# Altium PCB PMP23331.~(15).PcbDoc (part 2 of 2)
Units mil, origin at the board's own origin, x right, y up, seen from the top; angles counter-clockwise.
Board outline 3600 x 3375 mil, 4 copper layers (Top Layer, Signal Layer 1, Signal Layer 2, Bottom Layer), stack 39.6 mil thick; 105 components, 60 nets, 267 pads, 76 vias.

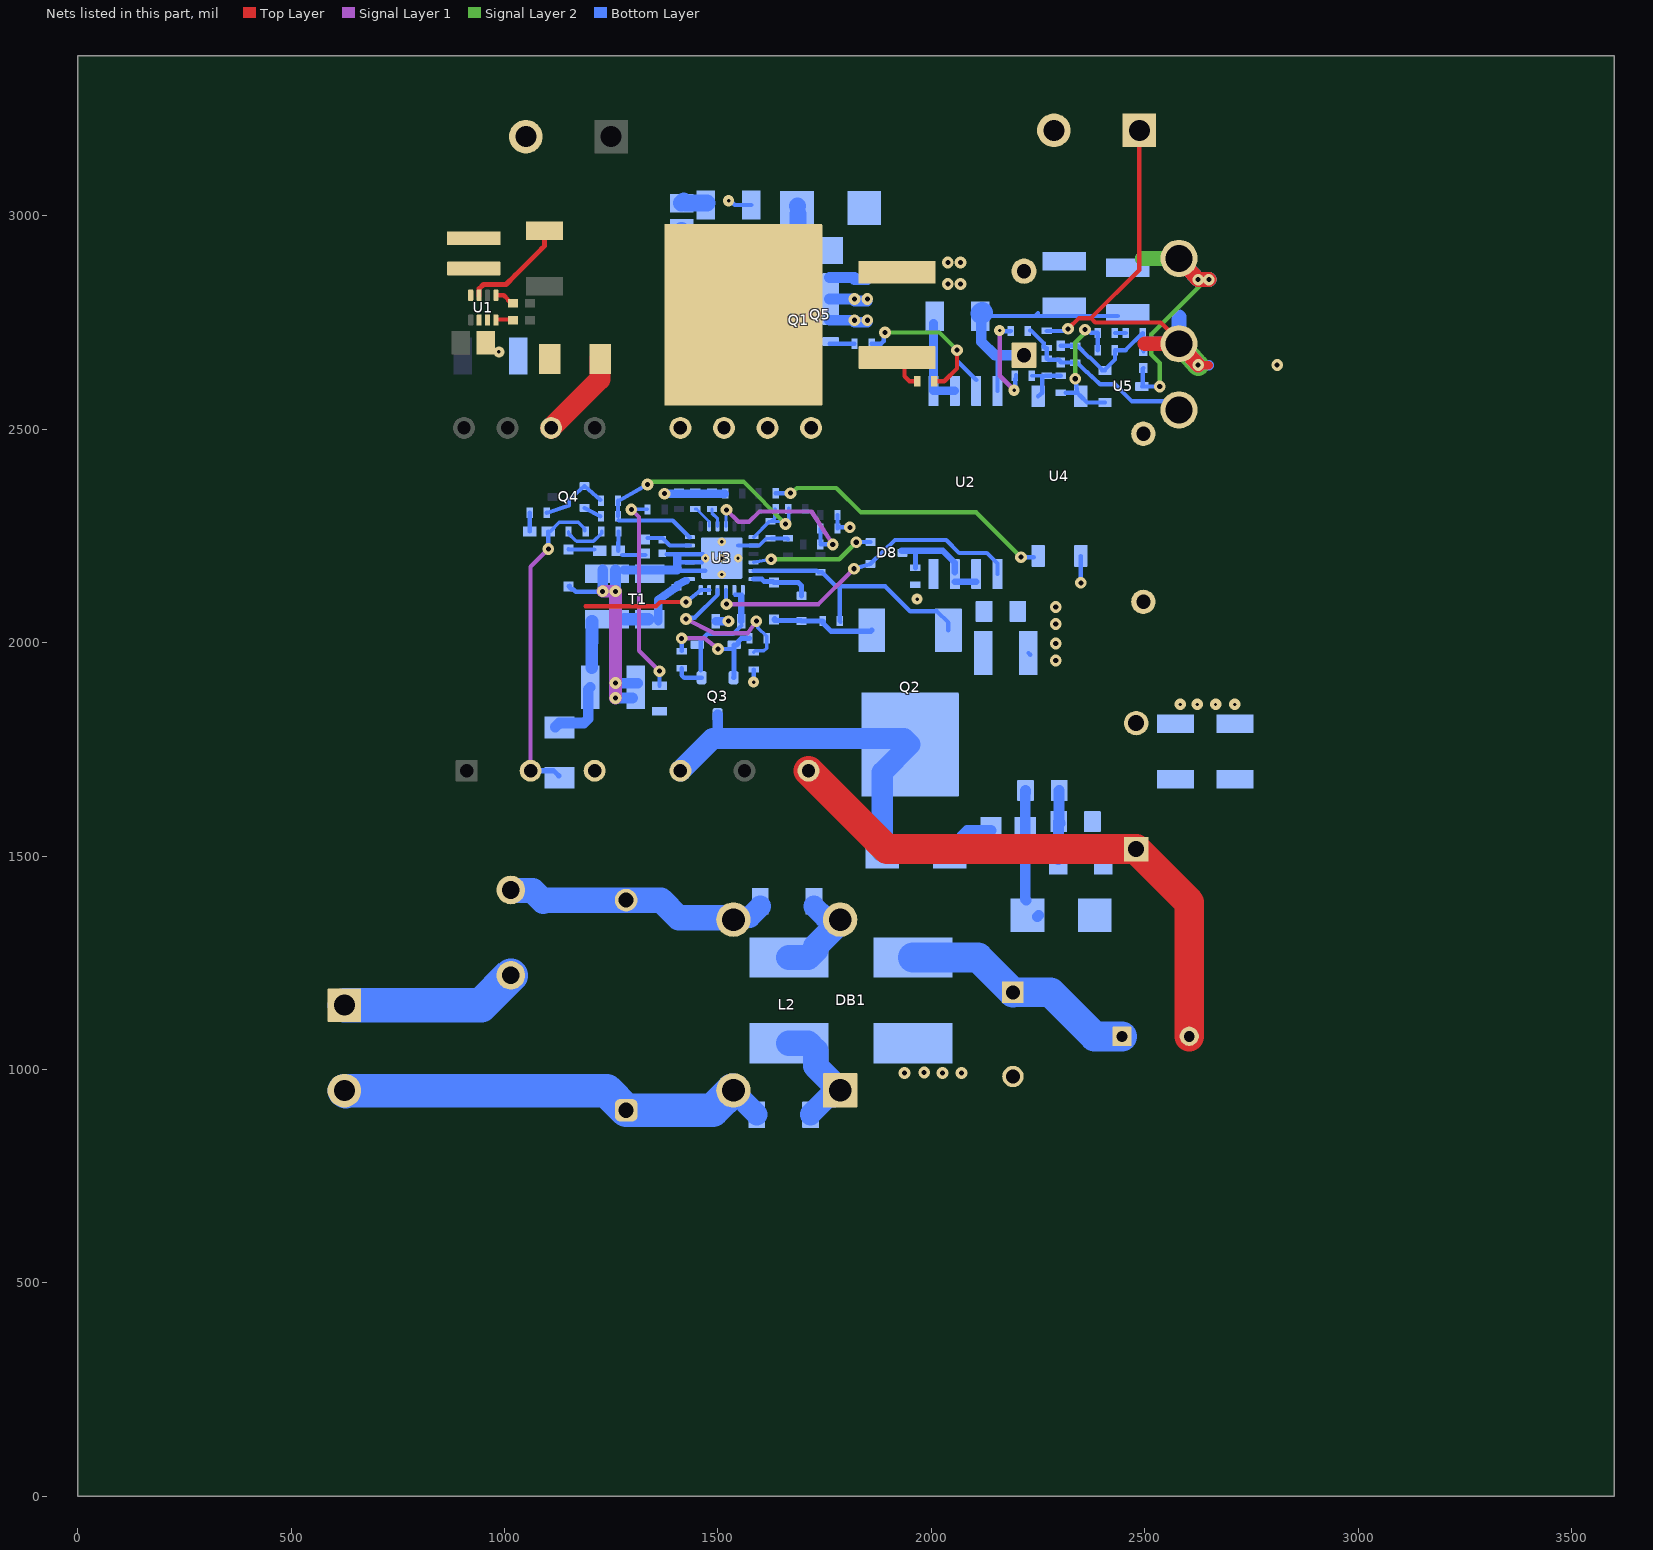
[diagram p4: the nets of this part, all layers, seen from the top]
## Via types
v1: diameter 27.56, hole 11.81, Top Layer to Bottom Layer, tented both sides, 30 vias
v2: diameter 27.56, hole 11.81, Top Layer to Bottom Layer, tented top, 22 vias
v3: diameter 26, hole 8, Top Layer to Bottom Layer, tented both sides, 11 vias
v4: diameter 19.68, hole 7.87, Top Layer to Bottom Layer, 5 vias
v5: diameter 27, hole 8, Top Layer to Bottom Layer, tented both sides, 4 vias
v6: diameter 27.56, hole 11.81, Top Layer to Bottom Layer, 4 vias

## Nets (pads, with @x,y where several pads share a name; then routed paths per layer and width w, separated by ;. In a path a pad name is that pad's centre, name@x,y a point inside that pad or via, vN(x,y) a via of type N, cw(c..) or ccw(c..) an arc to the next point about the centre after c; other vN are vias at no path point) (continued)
GND_P: C1.2 C3.1 C4.1 C5.1 C7.2 C13.1 C16.1 C17.2 C18.2 C19.1 C21.2 C23.2 C25.2 C26.2 C27.1 C31.2 D11.1 DB1.4 R10.2 R11.1 R22.1 R25.2 R29.1 R31.1 R34.1 RT1.2 T1.3 U2.4 U3.8 U3.17 U3.18 U3.20 U3.21 U3.22 U3.25 U4.4 | length 1676
  Top Layer w10: 1190,2085 1355,2085 1365,2095 v1(1425,2095)
  Signal Layer 1 w30: v2(1230,2120) v2(1260,2120) v2(1260,1870)
  Bottom Layer w7.87: C31.2@1612.58,2243.67 C31.2@1624.99,2243.67
  Bottom Layer w8: 1596.16,2227.25 C31.2@1612.58,2243.67
  Bottom Layer w8.66: U3.21@1434.16,2187.49 U3.21@1434.16,2187.88
  Bottom Layer w10: D11.1@1150,2131.69 D11.1@1151.69,2130 ; D11.1@1153,2133 1153,2128.69 1156.81,2124.88 1161.12,2124.88 1167,2119 v2@1230,2119 ; 1380,2207 U3.25@1465,2207 ; 1405,2188 U3.25@1462.6,2188 ; C17.2@1413.2,2168.2 U3.25@1470,2168.2 ; v1(1425,2095) U3.18@1459.75,2122.92 U3.17@1479.44,2122.92 ; C26.2@1516.51,2348.67 C26.2@1517.14,2349.3 ; U3.25@1547.35,2227.25 1596.16,2227.25 ; v3(1583.77,1907.47) C16.1@1583.77,1937 ; C31.2@1624.99,2243.67 1662.21,2243.67 C25.2@1664.11,2241.77 ; R34.1@1780,2267 R25.2@1780,2299 ; R34.1@1780,2270 v1(1809,2270) ; R11.1@2227.39,1975.71 R11.1@2231.46,1971.64 ; v2(2350,2140) U4.4@2350,2202.99
  Bottom Layer w20: C19.1@1280,2170 1405,2170 1405,2201.74 ; v1(1375,2348.67) C26.2@1516.51,2348.67 ; C23.2@1495,2050 v1(1525,2050)
  Bottom Layer w25: v2(1230,2120) C19.1@1230,2170 ; v2(1260,1870) C13.1@1300,1870 ; v2(1260,1905) C13.1@1312.35,1905 ; v2(1260,2120) C19.1@1260,2170
  other v2: 1936.75,992.02 2026.32,992.02 2070.71,992.02 1983.18,992.75 2291.34,1957.84 2291.34,1998.03 2291.34,2043.52 2291.34,2083.46
  other v3: 1966.65,2101.69
  other v4: 1508.96,2159.54 1470.78,2197.72 1508.96,2197.72 1547.15,2197.72 1508.96,2235.91
  other v5: 2582.5,1855 2622.5,1855 2665.6,1855 2711.01,1855
GND_S: C1.1 C8.2 C9.2 C10.2 C11.1 C20.2 D4.2 J2.2 Q1.1-2-3 Q5.3 R4.1 R36.1 TP2.1 U2.5 U2.6 U5.3 | length 1467.1
  Top Layer w35: TP2.1@2580,2900 v6(2625,2850) v6(2650,2850)
  Signal Layer 1 w35: TP2.1@2580,2900 v6(2625,2850) v6(2650,2850)
  Signal Layer 2 w10: v1(2535,2600) 2535,2655 2515,2675 2515,2722 v6@2641.5,2848.5
  Signal Layer 2 w35: 2495,2900 TP2.1@2580,2900 v6(2625,2850) v6(2650,2850)
  Bottom Layer w10: v3(1525,3035) 1529.33,3035 1539.33,3025 R4.1@1578.15,3025 ; R36.1@2496.65,2643.31 2494.98,2641.63 2494.98,2601.67 U5.3@2493.31,2600 v1(2535,2600)
  Bottom Layer w20: C20.2@2005,2748.43 U2.5@2005,2589.57 U2.6@2055,2589.57
  Bottom Layer w25: Q1.1-2-3@1761.22,2755 v2(1820,2755) ; Q1.1-2-3@1761.22,2805 v2(1820,2805) ; Q1.1-2-3@1761.22,2855 1820,2855 ; v2@1820,2750 v2@1850,2750 ; v2@1820,2800 v2@1850,2800 ; 1820,2850 1850,2850 ; v6(2625,2850) v6(2650,2850)
  Bottom Layer w35: 2495,2900 TP2.1@2580,2900 v6(2625,2850)
  other v2: 1850,2755 1850,2805 2038.5,2840.05 2068.5,2840.05 2038.5,2890.05 2068.5,2890.05
IPC: R32.1 R34.2 U3.4 | length 418
  Signal Layer 1 w10: v1(1519.8,2310.91) 1548,2283 1572.52,2283 1597.27,2307 1719,2307 v1(1769,2230)
  Bottom Layer w7.87: U3.4@1518.81,2272.53 1518.81,2309.92 v1(1519.8,2310.91)
  Bottom Layer w10: R32.1@1740,2230 v1@1775,2230 ; R32.1@1740,2235 R34.2@1740,2267
NetC2_2: C2.2 R1.1 R2.2 | length 164.3
  Bottom Layer w25: C2.2@2296.85,1490.98 2297.61,1491.74 2297.61,1579.92 R1.1@2298.38,1580.68 2298.02,1581.04 2298.87,1581.89 2298.87,1652.93 R2.2@2299.37,1653.43 ; R1.1@2301.33,1576.9 R1.1@2301.69,1577.26
NetC6_1: C6.1 J1.2 L2.2 R38.1 | length 1033.3
  Bottom Layer w50: L2.2@1536.31,951.02 1536.31,949.88 1591.01,895.18 R38.1@1591.01,894
  Bottom Layer w78.74: J1.2@627.75,947.72 J1.2@625,950.47 1238.94,950.47 C6.1@1285,904.41 1487.41,904.41 1533.65,950.65 1535.93,950.65 L2.2@1536.31,951.02
NetC6_2: C6.2 F1.1 L2.3 R37.1 | length 629
  Bottom Layer w50: L2.3@1536.31,1351.02 1542.18,1356.9 1574.3,1356.9 1599.21,1381.82 R37.1@1599.21,1383
  Bottom Layer w59.06: F1.1@1015,1420.47 1016.51,1418.97 1066.03,1418.97 1091,1394 1093.54,1396.54 C6.2@1285,1396.54 1366.83,1396.54 1408.19,1355.17 1532.16,1355.17 L2.3@1536.31,1351.02
NetC7_1: C7.1 DB1.1 L1.1 | length 566.3
  Bottom Layer w70: DB1.1@1957.34,1262.25 2109.18,1262.25 C7.1@2191,1180.43 ; C7.1@2190.68,1180.99 2279.01,1180.99 2382.35,1077.65 L1.1@2446.59,1077.65
NetC11_2: C11.2 C12.2 D4.1 Q1.5-6-7-8 Q5.4 T1.9 T1.10 | length 259.4
  Bottom Layer w39.37: 1415,2864 C12.2@1415,2965 ; 1429,2863 1451,2841 1451,2833 ; D4.1@1686.63,3022.63 D4.1@1687,3023 ; D4.1@1687.26,2987 1687.26,3003.26 1687.63,3003.63 1687.63,2906.37 C11.2@1691,2903
NetC12_1: C12.1 R4.2 | length 64.6
  Bottom Layer w39.37: C12.1@1415,3029.53 1415,3030 1420,3035 1425,3030 R4.2@1475,3030
NetC14_1: C14.1 C15.1 D6.1 U1.6 U1.7
  other v3: 987,2681
NetC21_1: C21.1 D8.3 U2.2 U2.3 | length 249.6
  Bottom Layer w12: 1960,2215 1962.37,2212.63 C21.1@1962.37,2175
  Bottom Layer w15: D8.3@1930,2215 1960,2215 2027,2215 2055,2186.94 U2.3@2055,2165 ; U2.3@2055,2142 U2.2@2105,2142
NetC24_1: C24.1 R28.2 | length 212.6
  Signal Layer 1 w10: v3@2159,2732 v3(2160,2731) 2160,2625 v3(2194,2591)
  Bottom Layer w10: v3@2167,2729 2185,2729 C24.1@2186,2730 ; v3(2194,2591) 2196.68,2593.68 2196.68,2617.47 2198,2618.79 R28.2@2198,2627
NetC28_1: C28.1 C29.2 R30.1 R35.2 R36.2 U5.2 | length 314.7
  Bottom Layer w10: R30.1@2303.15,2695.35 2303.31,2695.51 C28.1@2333.09,2695.51 ; C28.1@2337.06,2695.67 2333.25,2695.67 C28.1@2333.09,2695.51 ; R36.2@2496.65,2682.68 2496.65,2684.65 2495.83,2685.47 2495.83,2724.17 R35.2@2495,2725 2455,2685 C29.2@2430,2685 2430,2663.13 2406.69,2639.82 U5.2@2406.69,2637.4 2399.71,2637.4 2399.71,2639.46 2371.5,2667.67 2369.55,2667.67 2341.72,2695.51 C28.1@2333.09,2695.51
NetC29_1: C29.1 C30.2 R33.1 U4.3 U5.1 | length 331
  Signal Layer 2 w10: v1(2337,2618) 2337.09,2703 2360,2725.91 v1(2360,2733)
  Bottom Layer w10: R33.1@2315,2585 U4.3@2342.01,2585 ; v1(2337,2618) U4.3@2342.01,2585 ; v1(2360,2733) 2373.02,2725.91 2389.09,2725.91 C30.2@2390,2725 C29.1@2390,2685 ; U5.1@2406.69,2562.6 2364.41,2562.6 U4.3@2350,2577.01 U4.3@2342.01,2585
NetC30_1: C30.1 R35.1 | length 25
  Bottom Layer w10: C30.1@2430,2725 R35.1@2455,2725
NetD1_1: D1.1 R2.1 R3.2 | length 268.4
  Bottom Layer w25: R2.1@2220.63,1648.51 R2.1@2220.63,1653.43 2220.21,1653.01 2220.21,1560.29 R3.2@2219.8,1559.88 2219.8,1399.33 D1.1@2222.59,1396.54 ; D1.1@2248,1357.37 D1.1@2251.63,1361
NetD2_1: D2.1 R3.1 | length 121.9
  Bottom Layer w25: D2.1@2042.74,1510.66 2069.61,1537.53 2069.61,1545.23 2084.26,1559.88 R3.1@2139.8,1559.88
NetD5_2: D5.2 Q2.1 R6.2 R7.2 | length 246.9
  Bottom Layer w12: D5.2@1632.97,2055.66 D5.2@1631,2053.69 1632.61,2052.08 1694.39,2052.08 R6.2@1696,2050.47 R7.2@1745.07,2050.47 1746.57,2048.97 1746.57,2044.47 1764.57,2026.47 1857.85,2026.47 Q2.1@1860.24,2028.86
NetD6_2: D6.2 T1.12 | length 213.4
  Top Layer w25: D6.2@1224.26,2664.48 D6.2@1227.11,2661.63
  Top Layer w50: T1.12@1109.21,2502.75 1223.67,2617.21 1223.67,2663.89 D6.2@1224.26,2664.48
NetD7_1: D7.1 Q3.2 R8.1 R12.2 | length 280.8
  Signal Layer 1 w10: v1(1415,2010) 1468.25,2010 v1(1500,1985)
  Bottom Layer w10: R8.1@1415,1980 v1(1415,2010) ; v1(1500,1985) 1535,1985
  Bottom Layer w12: Q3.2@1536.6,1917.76 1537.45,1918.61 1537.45,1994.15 1543.36,1994.15 1548.06,1998.84 1548.06,2002.97 1555.08,2010 R12.2@1573.9,2010
NetD9_1: D9.1 R17.2 R19.2 | length 99
  Bottom Layer w10: D9.1@1266.65,2215 R17.2@1267,2260 ; D9.1@1276,2205 R19.2@1330,2205
NetD9_2: D9.2 D11.2 | length 60
  Bottom Layer w10: D11.2@1150,2218.31 D9.2@1210,2218
NetD10_1: D10.1 R20.2 | length 44
  Bottom Layer w10: R20.2@1059,2304 D10.1@1059.35,2260
NetDB1_2: DB1.2 L2.4 R37.2 | length 240.2
  Bottom Layer w50: R37.2@1725.2,1383 1725.2,1381.82 1750.12,1356.9 1780.43,1356.9 L2.4@1786.31,1351.02
  Bottom Layer w59.06: DB1.2@1666,1262.25 1711.28,1262.25 1728.99,1279.96 1728.99,1287.85 1786.31,1345.16 L2.4@1786.31,1351.02
NetDB1_3: DB1.3 L2.1 R38.2 | length 280.4
  Bottom Layer w50: R38.2@1716.99,894 1716.99,895.18 1757.48,935.67 1770.95,935.67 L2.1@1786.31,951.02
  Bottom Layer w59.06: DB1.3@1666,1061.46 1711.28,1061.46 1728.99,1043.74 1728.99,1008.34 L2.1@1786.31,951.02
NetF1_2: F1.2 J1.1 | length 419
  Bottom Layer w80: J1.1@625,1150.47 945,1150.47 F1.2@1015,1220.47
NetL3_1: L3.1 U1.4
NetQ1_4: Q1.4 R5.2 | length 58.8
  Bottom Layer w10: Q1.4@1761.22,2700 R5.2@1820,2700
NetQ4_1: Q4.1 R16.2 R20.1 | length 166.2
  Bottom Layer w10: R20.1@1099,2304 1150.94,2321 1150.94,2335 Q4.1@1187.42,2366.59 R16.2@1224.37,2334
NetQ4_2: Q4.2 R15.2 | length 41.7
  Bottom Layer w10: Q4.2@1187.42,2315.41 R15.2@1224.37,2296
NetQ5_1: Q5.1 R39.2 | length 87
  Top Layer w10: Q5.1@1937,2676 1937,2624 1949,2612 R39.2@1967,2612
NetR9_2: R9.2 U1.1 | length 43.6
  Top Layer w10: U1.1@980,2813.62 998.2,2813.62 1008.5,2803.31 1008.5,2801.34 1013.35,2796.5 R9.2@1015.31,2796.5
NetR13_2: R13.2 U1.8 | length 37
  Top Layer w10: U1.8@980,2755.35 980,2756.03 980.91,2756.93 1013.69,2756.93 R13.2@1015.28,2758.51
NetR14_1: R14.1 R17.1 | length 102.7
  Bottom Layer w8: R14.1@1150,2260 1150,2255.5 1165.38,2240.12 1165.95,2240.12 1169.07,2237 1208.5,2237 1228,2256.5 R17.1@1228,2261
NetR26_1: R26.1 R28.1 R33.2 U4.1 | length 121
  Bottom Layer w7.87: R28.1@2235,2625 2260,2625 R26.1@2267,2625
  Bottom Layer w10: U4.1@2250,2577.01 2260,2585 R26.1@2260,2625 ; R26.1@2267,2625 R26.1@2270,2625 R33.2@2303.15,2625
OPTO_C: R21.2 U4.6 | length 676
  Signal Layer 2 w10: v1(1670,2350) 1685,2362 1777,2362 1835,2305 2105,2305 v2(2210,2200)
  Bottom Layer w10: R21.2@1635,2350 v1(1670,2350) ; v2(2210,2200) U4.6@2240,2200
P13: C23.1 D7.2 Q3.1 R8.2 U3.13 U3.14 | length 320.3
  Bottom Layer w10: R8.2@1415,1940 1415,1923.61 1420.86,1917.76 Q3.1@1461.79,1917.76 ; 1460,1935 1460,2005 1475,2020 1535,2020 C23.1@1555,2040 ; U3.14@1540,2112 U3.13@1556.22,2111.97
  Bottom Layer w15: C23.1@1555,2050 1555,2109
PWML: D5.1 R6.1 U3.12 | length 142.3
  Bottom Layer w12: U3.12@1583.77,2148.51 1602.65,2148.51 1608.39,2142.77 1628.53,2142.77 D5.1@1631,2140.31 1688.97,2140.31 1696,2133.28 R6.1@1696,2109.53
QLSRC: Q2.3 R7.1 R10.1 R11.2 R23.2 U3.11 | length 609.1
  Bottom Layer w10: U3.11@1583.77,2168.2 1731.71,2168.2 1735.5,2164.41 R23.2@1740,2164.41 1744.5,2164.41 1777.22,2131.69 1787.5,2131.69 ; R7.1@1787.04,2048.5 R7.1@1785.07,2050.47 1785.07,2129.27 1787.5,2131.69 ; Q2.3@2039.76,2028.86 2039.76,2046.65 2013.27,2073.15 1950.45,2073.15 1891.91,2131.69 1787.5,2131.69
RDM: R31.2 U3.3 | length 45.8
  Bottom Layer w7.87: R31.2@1485.96,2312.88 1485.96,2303.52 1499.12,2290.36 U3.3@1499.12,2272.53
REF: C22.1 C31.1 R15.1 R16.1 R24.1 U3.7 U3.24 | length 839.7
  Signal Layer 2 w9.84: 1560,2377 v1(1658,2278) ; v1@1659.44,2269.49 v1@1664.53,2274.58
  Signal Layer 2 w10: v1@1340,2377 1560,2377
  Bottom Layer w8: U3.7@1583.77,2246.94 1620.5,2283.67 C31.1@1624.99,2283.67 ; C22.1@1634.9,2312.88 1632.61,2312.88 1632.61,2291.29 C31.1@1624.99,2283.67 ; R24.1@1665.76,2314.85 1665.76,2275.81 1664.53,2274.58 1655.44,2283.67 C31.1@1624.99,2283.67
  Bottom Layer w9.84: U3.24@1432.72,2246.94 U3.24@1434.16,2246.94
  Bottom Layer w10: R15.1@1266,2296 R16.1@1266,2332 ; R16.1@1266,2331 v1(1335,2370) ; R15.1@1267.65,2286 1394,2286 U3.24@1432.72,2246.94
RT1_1: R27.1 RT1.1 | length 487.6
  Signal Layer 1 w9.84: v1(1297,2312) 1315,2294 ; v1@1297.34,2310.91 v1@1306.49,2310.91
  Signal Layer 1 w10: 1315,2294 1315,1981 v1(1363,1933)
  Bottom Layer w8: v1(1297,2312) R27.1@1335,2312
  Bottom Layer w10: RT1.1@1362.93,1898.9 v1(1363,1933)
RTZ: R29.2 U3.2 | length 56
  Bottom Layer w6: R29.2@1446.59,2312.88 1450.15,2312.88 1479.44,2283.59 U3.2@1479.44,2272.53
RUN: D8.2 U3.10 | length 301.1
  Signal Layer 2 w9.84: v1(1624.74,2195.03) 1784,2195
  Signal Layer 2 w10: 1784,2195.03 v1(1824,2235)
  Bottom Layer w7.87: U3.10@1583.77,2187.88 v1(1624.74,2195.03) v1@1617.59,2187.88
  Bottom Layer w10: v1(1824,2235) D8.2@1857.6,2235.59
SR_DRV: R5.1 R39.1 U2.7 | length 440.6
  Top Layer w10: R39.1@2004.5,2614.5 R39.1@2007,2612 ; R39.1@2005,2612 R39.1@2007,2612 ; v1(2060,2685) 2060,2642 2030,2612 R39.1@2007,2612
  Signal Layer 2 w10: v1(1891.51,2726.26) 2018.74,2726.26 v1(2060,2685)
  Bottom Layer w10: R5.1@1860,2700 1882.29,2700 1888.15,2705.86 1888.15,2722.9 v1(1891.51,2726.26) ; v1(2060,2685) 2060,2660 U2.7@2105,2615
SRDRV: D8.1 U2.1 U3.15 | length 773.7
  Signal Layer 1 w10: v1(1520,2090) 1735.67,2090 v1(1818.64,2172.96)
  Bottom Layer w10: v1@1519,2090 U3.15@1519,2123 ; v1(1818.64,2172.96) D8.1@1857.6,2184.41 1915,2240 2035,2240 2065,2210 2130,2210 U2.1@2155,2185 ; U2.1@2155,2160.43 U2.1@2155,2184.84
SWS: C16.2 R12.1 U3.16 | length 403.4
  Signal Layer 1 w10: v1(1425,2055) 1490,2022 1570,2022 v1(1590,2050)
  Bottom Layer w8: C16.2@1583.77,1977 1587.27,1980.5 1607.58,1980.5 1613.9,1986.82 R12.1@1613.9,2010 1613.9,2014.5 1593.74,2034.66 1593.74,2046.26 v1(1590,2050)
  Bottom Layer w10: v1(1425,2055) 1428.36,2058.36 1445.8,2058.36 1499.12,2111.68 U3.16@1499.12,2122.92
Vaux: D3.2 D10.2 R14.2 T1.2 | length 760
  Signal Layer 1 w10: T1.2@1061.21,1699.75 1061.21,2177.55 v1(1102.65,2219)
  Bottom Layer w8: D10.2@1102.65,2260 1106.59,2260 1128.59,2282 1172.5,2282 1188,2266.5 R14.2@1188,2262
  Bottom Layer w10: T1.2@1058.56,1686.84 T1.2@1065.13,1686.84 ; v1(1102.65,2219) D10.2@1102.65,2260
  Bottom Layer w12: T1.2@1061.21,1699.75 1115.25,1699.75 D3.2@1127,1688
Vbulk: C2.1 C3.2 C4.2 C5.2 D1.2 L1.2 R1.2 T1.6 | length 1333.6
  Top Layer w70: T1.6@1712.21,1699.75 1895.93,1516.03 C5.2@2479.8,1516.03 2604.07,1391.76 L1.2@2604.07,1077.65
VDD: C13.2 C17.1 C18.1 C19.2 D3.1 U3.19 | length 451.9
  Bottom Layer w18: C17.1@1405,2135 U3.19@1425,2145
  Bottom Layer w20: C18.1@1360,2050 1360,2100 C17.1@1403,2130
  Bottom Layer w25: D3.1@1119,1802.06 1128.41,1811.46 1185.78,1811.46 1196.18,1821.86 1196.18,1890.19 C13.2@1201,1895 ; D3.1@1126.34,1808.29 D3.1@1128.75,1810.7
  Bottom Layer w30: C13.2@1204.46,1941.82 C19.2@1205,2050 ; C19.2@1281.04,2054.85 C18.1@1336.04,2054.85
VOUT: C8.1 C9.1 C10.1 C20.1 J2.1 R18.1 T1.7 T1.8 TP1.1 U2.8 | length 1961.6
  Top Layer w10: v1(2320,2735) 2346,2760 2374,2760 ; J2.1@2487,3200 2487,2873 2374,2760 ; TP1.1@2580,2700 2580,2706.97 2537.36,2750 2384,2750.05 2374,2760
  Top Layer w20: v6(2625,2650) 2650,2650
  Top Layer w35: 2500,2700 TP1.1@2580,2700 v6(2625,2650)
  Signal Layer 1 w20: v6(2625,2650) 2650,2650
  Signal Layer 1 w35: 2505,2700 TP1.1@2580,2700 v6(2625,2650)
  Signal Layer 2 w50: TP1.1@2580,2700 v6(2625,2650)
  Bottom Layer w10: 2141.93,2765 2243.15,2765 ; U2.8@2155,2589.57 2155,2673 ; C10.1@2217,2673 C10.1@2218.93,2674.93 ; 2250,2771.85 2243.15,2765 ; R18.1@2270,2730 2310,2730 v1(2320,2735) ; C9.1@2436.8,2765 2243.15,2765
  Bottom Layer w25: C20.1@2117,2761 2117,2705 2149,2673 2155,2673 C10.1@2217,2673 ; v6@2625.32,2650 2650,2650
  Bottom Layer w35: 2580,2762.93 TP1.1@2580,2700 v6(2625,2650)
  Bottom Layer w50: C20.1@2117,2771 C20.1@2119,2773
  other v6: 2810,2650
VOUT2: C32.1 J3.2 L3.2 U1.3 | length 258.3
  Top Layer w12: U1.3@940.63,2813.62 940.72,2813.71 940.72,2828.95 950.58,2838.81 1003.43,2838.81 1025.28,2860.65 1087.13,2922.5 1094.16,2929.53 C32.1@1094.16,2964.96
  Top Layer w25: J3.2@1050,3172.59 J3.2@1050,3185
VOUT_A: C24.2 C28.2 R18.2 R26.2 R30.2 TP3.1 | length 448
  Bottom Layer w10: C24.2@2231,2731 2233.5,2731 2263,2701.5 2263,2692.5 2265.5,2690 R18.2@2270,2690 R26.2@2270,2666.65 ; R26.2@2270,2665 R26.2@2270,2666.65 ; R30.2@2303.15,2655.98 R30.2@2303.15,2657.66 ; TP3.1@2580,2545 2560,2565 2470,2565 2430,2605 2395.28,2605 2365,2634 2363.23,2634 2341.4,2655.83 2304.98,2655.83 R30.2@2303.15,2657.66 ; R26.2@2270,2666.65 2274.15,2662.5 2298.31,2662.5 R30.2@2303.15,2657.66
VS: R19.1 R22.2 U3.23 | length 106.7
  Bottom Layer w10: R19.1@1335,2245 1370,2245 1387,2227.25 U3.23@1434.16,2227.25
VSWN: D2.2 Q2.2 Q3.3 T1.4 | length 912.7
  Bottom Layer w25: 1488.12,1775.34 1499.2,1786.42 Q3.3@1499.2,1831.14
  Bottom Layer w50: T1.4@1412.21,1699.75 1412.53,1699.75 1488.12,1775.34 1935.8,1775.34 Q2.2@1950,1761.14 1885.26,1696.4 D2.2@1885.26,1510.66
pads on no net: T1.1 T1.5 T1.11 T1.13 U1.2

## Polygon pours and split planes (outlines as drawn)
GND_S on Bottom Layer "Bottom Layer-SGND" (solid, remove dead copper, pour order 307): 1384,3074 1384,2915 1733.02,2915 1733.02,2554.28 2071.4,2554.28 2071.4,2830 2825,2830 2825,3074
NetC14_1 on Bottom Layer "BOTTOM_LAYER_NETC14_1_P358" (solid, remove dead copper, pour order 358): 972,2715 972,2615 1053,2615 1057,2615 1057,2621 1057,2715
GND_C on Bottom Layer "BOTTOM_LAYER_GND_C_P357" (solid, remove dead copper, pour order 357): 838,2771 838,2469 933,2469 933,2771
GND_P on Bottom Layer "BOTTOM_LAYER_GND_P_P356" (solid, remove dead copper, pour order 356): 1247,1948 1247,1842 1265,1824 1386,1824 1386,1860 1371,1875 1341,1875 1334,1882 1335,1883 1335,1948
NetC11_2 on Bottom Layer "BOTTOM_LAYER_NETC11_2_P345" (solid, remove dead copper, pour order 345): 1347.76,2693.98 1347.76,2465 1562.21,2465 1562.21,2610.81 1613.9,2662.5 1616.4,2660 1720,2660 1720,2775 1428.78,2775
Vbulk on Bottom Layer "BOTTOM_LAYER_VBULK_P344" (solid, remove dead copper, pour order 344): 2335.98,1350 2335.98,1276.27 2572.13,1040.12 2820,1040.12 2820,1627.91 2338.41,1627.91
GND_P on Bottom Layer "BOTTOM_LAYER_GND_P_P343" (solid, remove dead copper, pour order 343): 2179.23,2226.84 2179.8,2226.28 2179.8,1797.67 2216.32,1761.14 2834.99,1761.14 2834.99,2226.84
Vbulk on Bottom Layer "BOTTOM_LAYER_VBULK_P342" (solid, remove dead copper, pour order 342): 2334.95,1351.02 2335.98,1350 2609.32,1350 2820,1560.68 2820,1718.98 2441.07,1718.98 2350,1627.91 2350,1470.08 2334.95,1455.04
GND_P on Bottom Layer "BOTTOM_LAYER_GND_P_P341" (solid, remove dead copper, pour order 341): 1948.59,2155 1976.15,2155 1976.15,2187.72 1986.19,2197.76 2023.28,2197.76 2035,2186.04 2035,2107.22 2000.93,2073.15 1950.45,2073.15
QLSRC on Bottom Layer "BOTTOM_LAYER_QLSRC_P340" (solid, remove dead copper, pour order 340): 2000.93,2100 2002.62,2101.69 2155,2101.69 2155,1922.56 2152.69,1920.25 2048.72,1920.25 2000.93,1968.04
GND_S on Bottom Layer "BOTTOM_LAYER_GND_S_P335" (solid, remove dead copper, pour order 335): 2239.06,3375 2825,3375 2825,2938 2239.06,2938
GND_P on Bottom Layer "BOTTOM_LAYER_GND_P_P319" (solid, remove dead copper, pour order 319): 1867.07,1151.02 2066.22,1151.02 2117.25,1100 2242.34,1100 2252.34,1090 2252.34,952.34 2230,930 1909.76,930 1867.07,972.69
VOUT on Bottom Layer "BOTTOM_LAYER_VOUT_P314" (solid, remove dead copper, pour order 314): 2825,2820 2825,2630 2515,2630 2515,2755 2090,2755 2090,2820
NetC11_2 on Bottom Layer "Bottom Layer-NetC33_2" (solid, pour order 303): 1395,2660 1395,2934 1720,2934 1720,2660
GND_C on Signal Layer 2 "SIGNAL_LAYER_2_GND_C_P351" (solid, remove dead copper, pour order 351): 846.9,2465 846.9,3375 848.83,3373.08 1296,3373.08 1296,2976.48 1274.79,2955.28 1274.79,2610.29 1134.5,2470
GND_S on Signal Layer 2 "SIGNAL_LAYER_2_GND_S_P338" (solid, remove dead copper, pour order 338): 2243.65,3375 2243.65,2869.98 2825,2869.98 2825,3375
GND_S on Signal Layer 2 "Signal Layer 2-SGND" (solid, pour order 292): 1363,2911.72 1363,2583.92 1471.92,2475 2700,2475 2825,2600 2825,3070.19 1521.11,3069.83
GND_P on Signal Layer 2 "SIGNAL_LAYER_2_GND_P_P293" (solid, remove dead copper, pour order 293): 1374.42,2365 1374.42,1541.23 2834.99,1541.23 2834.98,2176.53 2646.52,2365
GND_P on Signal Layer 2 "SIGNAL_LAYER_2_GND_P_P291" (solid, remove dead copper, pour order 291): 928,2390 928,1545.17 1765.07,1545.17 1769.08,2390
GND_P on Signal Layer 2 "SIGNAL_LAYER_2_GND_P_P290" (solid, remove dead copper, pour order 290): 1900.33,1576.66 1900.33,880 2826.83,880 2826.83,1576.66
GND_C on Signal Layer 1 "SIGNAL_LAYER_1_GND_C_P352" (solid, remove dead copper, pour order 352): 846.9,2467.98 846.9,3377.98 848.83,3376.05 1303,3376.05 1303,2986.46 1274.79,2958.25 1274.79,2613.27 1134.5,2472.98
VOUT on Signal Layer 1 "SIGNAL_LAYER_1_VOUT_P337" (solid, remove dead copper, pour order 337): 2372.3,2945.9 2374,2947.6 2374,3380.9 2826.83,3380.9 2826.83,2657.08 2662.31,2657.08 2386.29,2657.08
GND_P on Signal Layer 1 "SIGNAL_LAYER_1_GND_P_P289" (solid, remove dead copper, pour order 289): 1416.08,2301.91 1416.08,1540.41 2834.99,1540.41 2834.98,2301.91
VOUT on Signal Layer 1 "Signal Layer 1-VN" (solid, pour order 288): 1363,2519.02 1407.02,2475 2700,2475 2834.99,2609.99 2834.98,2814.63 2578.63,3071 1363,3071
GND_P on Signal Layer 1 "SIGNAL_LAYER_1_GND_P_P287" (solid, remove dead copper, pour order 287): 928,2389 928,1545.17 1781,1545.17 1781,2389
VOUT on Top Layer "TOP_LAYER_VOUT_P355" (solid, remove dead copper, pour order 355): 1574.3,2555.1 1575.13,2554.28 1575.13,2465 1841.54,2465 1850,2473.46 1850,2557.79
VOUT on Top Layer "Top Layer-VN" (solid, pour order 336): 1799.49,2975 1799.49,2465 2690,2465 2826.83,2601.83 2826.83,2747 2598.83,2975
GND_S on Top Layer "TOP_LAYER_GND_S_P283" (solid, remove dead copper, pour order 283): 2243.65,3375 2243.65,3072.1 1796.43,3071.91 1796.43,2737.64 1799.49,2734.58 1799.91,2735 2239.56,2735 2375.7,2871.14 2375.7,3375
NetC11_2 on Top Layer "TOP_LAYER_NETC11_2_P354" (solid, remove dead copper, pour order 354): 1374.42,3003.15 1375,3002.57 1375,2475 1548.9,2475 1550.93,2472.98 1550.93,2551.21 1753.3,2551.21 1753.3,3003.15
GND_C on Top Layer "TOP_LAYER_GND_C_P353" (solid, remove dead copper, pour order 353): 1035,2719 1039.59,2714.41 1292.41,2714.41 1292.41,2972.9 1358,3038.48 1358,3371.15 1354.15,3375 1162.51,3375 1162.51,2928.24 1149.27,2915 1093.39,2915 1035,2856.61
GND_C on Top Layer "TOP_LAYER_GND_C_P350" (solid, remove dead copper, pour order 350): 836.9,2475 846.9,2465 939.33,2465 939.33,2539.88 928,2551.21 928,2733.95 935.05,2741 935.05,2774.1 924.67,2784.48 836.9,2784.48
VOUT2 on Top Layer "TOP_LAYER_VOUT2_P349" (solid, remove dead copper, pour order 349): 856.15,3375 1151.5,3375 1151.5,2931.63 1149.27,2929.4 856.15,2929.53
NetL3_1 on Top Layer "TOP_LAYER_NETL3_1_P348" (solid, remove dead copper, pour order 348): 856.15,2847.52 907.17,2796.5 932.07,2796.5 932.07,2824.07 940,2845.77 992.72,2845.77 999.85,2852.9 999.85,2900 856.15,2900
NetC14_1 on Top Layer "TOP_LAYER_NETC14_1_P347" (solid, remove dead copper, pour order 347): 928,2770.7 928,2621.18 1165.21,2621.18 1165.21,2699.92 992.68,2699.92 980,2712.6 980,2770.7
VOUT on Top Layer "TOP_LAYER_VOUT_P346" (solid, remove dead copper, pour order 346): 2374,2940 2375.7,2941.7 2375.7,3375 2826.83,3375 2826.83,2651.18 2664.01,2651.18 2387.99,2651.18
GND_P on Top Layer "TOP_LAYER_GND_P_P284" (solid, remove dead copper, pour order 284): 1874.48,2226.84 1874.48,1755.91 2834.99,1755.75 2834.98,2141.48 2749.62,2226.84
GND_P on Top Layer "TOP_LAYER_GND_P_P285" (solid, remove dead copper, pour order 285): 940,2390 940,1887.57 1886.5,1887.57 1886.5,2390

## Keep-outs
Keep-Out Layer:
  text ".Layer_Name" at 577,-858.49 h60

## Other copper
Top Layer:
  pour cut-out: 1112.63,2238.27 1018,2238.27 1018,1917.79 1018,1650 1112.63,1650
  pour cut-out: 1245,2270 1447.21,2270 1447.21,2185.87 1347.46,2185.87 1339.83,2193.5 1245,2193.5
  pour cut-out: 2374,2772.45 2468.81,2872.24 2474,2877.44 2474,3159 2496.65,3159 2496.65,2872.24 2389.97,2765.56 2389.97,2763.03
  pour cut-out: 2380.55,2772.45 2389.97,2763.03 2547.64,2763.03 2570.31,2740.59 2547,2717.28 2529,2736.67 2358.7,2736.67 2336.23,2714.2 2295.79,2714.2 2295.79,2747.13 2318.85,2772.45
  pour cut-out: 1431.86,2328 1509,2328 1509,2259 1470,2259 1470,2284.16 1453.16,2301 1431.86,2301
  pour cut-out: 1285,2145 1205,2145 1205,2095 1235,2095 1285,2095
  pour cut-out: 1235,1930 1285,1930 1285,1845 1235,1845
  text ".Layer_Name" at 577,-858.49 h60
Signal Layer 1:
  pour cut-out: 1113.63,2237.5 1019,2237.5 1019,1917.02 1019,1649.23 1113.63,1649.23
  pour cut-out: 1245,2270 1447.21,2270 1447.21,2185.87 1347.46,2185.87 1339.83,2193.5 1245,2193.5
  pour cut-out: 1245,2270 1447.21,2270 1447.21,2185.87 1347.46,2185.87 1339.83,2193.5 1245,2193.5
  pour cut-out: 2296.39,2714.17 2345,2714.17 2345,2758.48 2296.39,2758.51
  pour cut-out: 1432,2328.11 1509,2328.11 1509,2259 1470,2259 1470,2284.16 1453.16,2301 1432,2301
  pour cut-out: 1285,2145 1205,2145 1205,2095 1235,2095 1235,1845 1285,1845
Signal Layer 2:
  pour cut-out: 1117.6,2241.37 1022.97,2241.37 1022.97,1920.9 1022.97,1653.1 1117.6,1653.1
  pour cut-out: 1245,2270 1447.21,2270 1447.21,2185.87 1347.46,2185.87 1339.83,2193.5 1245,2193.5
  pour cut-out: 1245,2270 1447.21,2270 1447.21,2185.87 1347.46,2185.87 1339.83,2193.5 1245,2193.5
  pour cut-out: 1245,2270 1447.21,2270 1447.21,2185.87 1347.46,2185.87 1339.83,2193.5 1245,2193.5
  pour cut-out: 1432,2328 1509,2328 1509,2259 1470,2259 1470,2283 1452,2301 1432,2301
  pour cut-out: 1235,1930 1285,1930 1285,1845 1235,1845
  pour cut-out: 1285,2145 1205,2145 1205,2095 1235,2095 1285,2095
Bottom Layer:
  text ".Layer_Name" at 577,-858.49 h60

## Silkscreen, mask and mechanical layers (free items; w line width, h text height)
Top Overlay:
  lines w7.87: 1148.49,2393.06 1148.49,2459.5
  lines w10: 40,910 60,850 ; 40,3070 60,3130 ; 50,850 70,850 ; 50,3130 70,3130 ; 60,1710.09 60,850 ; 60,2269.91 60,3130 ; 80,910 60,850 ; 80,3070 60,3130 ; 790,740 790,760 ; 850,730 790,750 ; 850,770 790,750 ; 867,3176 917,3176 ; 892,3151 892,3201 ; 1376.6,3180.05 1426.6,3180.05 ; 1565.08,750 790,750 ; 2114.92,750 2890,750 ; 2121.07,3190 2171.07,3190 ; 2605.5,3190 2655.5,3190 ; 2630.5,3165 2630.5,3215 ; 2830,730 2890,750 ; 2830,770 2890,750 ; 2890,740 2890,760
  lines w30: 2107.25,902.57 ccw(c2191.77,1083.83) 2276.3,902.57
  text "DC Output" at 1471,3272 h90
  text "DC Output" at 2734,3264 h90
  text "5V,0.2A" at 1493,3168 h90
  text "12V,1.5A" at 2756,3160 h90
  text "GND_S" at 2603,2780 h40
  text "VOUT" at 2623,2613 h40
  text "2280 (mil)" at 94.99,1720.09 h60 r90
  text "+" at 2673,1288 h60
  text "LINE" at 307.73,1180 h40
  text "NEUT" at 307.73,980 h40
  text "J1: AC Input" at 365,775 h90
  text "2100 (mil)" at 1575.08,715.01 h60
  text "DANGER HIGH VOLTAGE" at 1371,577 h100
  text ".Layer_Name" at 577,-858.49 h60
Bottom Overlay:
  lines w5: 1078,2406 1078,2336.54 1093.54,2321 ; 1315.31,2392.83 1315.31,2349.69 1330,2335 ; 1402,1993 1432,1993 ; 1412.17,2075 1441.83,2075 ; 1588.78,2399 1597,2372 ; 1638.09,2287.18 1650,2295 1650,2360 1639.83,2376 ; 1667,2034 1677,1986 ; 1719,2249 1719,2351 ; 1775.98,2318.91 1796.43,2332 ; 1790,2281 1803,2293 ; 2300.5,2569 2316.78,2548 2383,2548 2399.37,2529 ; 2395,2745 2395,2910 ; 2515,2745 2535.12,2765.12 2535.12,2807.49
  lines w7: 1422,2265 1422,2284 ; 1422,2285 1442,2285
  lines w10: 2163,2859 2163,2822 2196,2789 2223,2789 ; 2225,2788 2270,2743
  text "CAUTION" at 3400,2100 h100
  text "HOT SURFACE" at 3405,2010 h100
  text "DANGER" at 774,1372 h100
  text "HIGH VOLTAGE" at 773,1286 h100
  text "L" at 775,1114 h100
  text "TP1" at 1111,1089 h72.83
  text "TP2" at 1107,1001 h72.83
  text "N" at 794,917 h100
  text "DANGER" at 3500,850 h100
  text "HIGH VOLTAGE" at 3500,750 h100
  text ".Layer_Name" at 577,-858.49 h60
Top Paste:
  text ".Layer_Name" at 577,-858.49 h60
Bottom Paste:
  text ".Layer_Name" at 577,-858.49 h60
Top Solder:
  text ".Layer_Name" at 577,-858.49 h60
  text ".Layer_Name" at 577,-858.49 h60
Bottom Solder:
  text ".Layer_Name" at 577,-858.49 h60
Drill Guide:
  text ".Layer_Name" at 577,-858.49 h60
M1 Board Outline:
  drawing of 305 lines, arcs and shapes, not listed
  text ".Layer_Name" at 577,-858.49 h60
M2 Board Dimensions:
  rectangle: 125,-400 500,-275
  rectangle: 0,-275 125,-150
  lines w7: 0,-275 1000,-275 ; 125,-400 125,-150 ; 250,-400 250,-150 ; 500,-400 500,-150 ; 750,-400 750,-150 ; 0,-400 0,-150 1000,-150 1000,-400 0,-400
  text ".Layer_Name" at 577,-858.49 h60
M3 3D STEP Top:
  text ".Layer_Name" at 577,-858.49 h60
M4 3D STEP Bottom:
  text ".Layer_Name" at 577,-858.49 h60
M5 Assembly Top:
  lines w10: -292,-930.17 6308,-930.17 ; -292,-726.83 6310,-726.83 ; -292,-523.5 -292,-1133.5 3713,-1133.5 6310,-1133.5 6310,-523.5 -291.5,-523.5 -291.5,-1133.5 1284,-1133.5 ; 2173,-1133.5 2173,-523.5 ; 3440,-726.83 3440,-523.5 ; 4280,-726.83 4280,-523.5 ; 4902,-1140 4902,-937.17
  text "COMPONENTS MARKED 'DNP' SHOULD NOT BE POPULATED." at 1153.5,-318.5 h60
  text "ASSEMBLY VARIANT:" at 1153,-434 h60
  text ".VariantName" at 2189,-434 h60
  text "PCB VIEWED FROM TOP SIDE" at -228.5,-655.67 h60
  text "BOARD #:" at 2248,-655.67 h60
  text ".PRJ_Number" at 2793.5,-655.67 h60
  text "REV:" at 3638,-655.67 h60
  text ".PCB_Rev" at 3929.5,-655.67 h60
  text "SVN REV:" at 4476,-655.67 h60
  text ".VersionControl_RevNumber" at 4982,-655.67 h60
  text "TID #:" at 2248,-859 h60
  text ".TID" at 2793.5,-859 h60
  text "PLOT NAME =" at -228.5,-1064.34 h60
  text ".plot_File_Name" at 577,-1064.34 h60
  text "GENERATED    :" at 2250,-1064.34 h60
  text ".Print_Date" at 3119.5,-1064.34 h60
  text ".Print_Time" at 3848.5,-1064.34 h60
  text "TEXAS INSTRUMENTS" at 5113,-1064.34 h60
M6 Assembly Bottom:
  lines w10: -292.5,-727.33 6309.5,-727.33 ; -290.5,-930.67 6309.5,-930.67 ; 1115.5,-1140.5 1115.5,-937.67 ; 1737.5,-727.33 1737.5,-524 ; 2577.5,-727.33 2577.5,-524 ; 3844.5,-1134 3844.5,-524 ; 4733.5,-1134 6309,-1134 6309,-524 -292.5,-524 -292.5,-1134 2304.5,-1134 6309.5,-1134 6309.5,-524
  text "COMPONENTS MARKED 'DNP' SHOULD NOT BE POPULATED." at 6102,-318 h60
  text ".VariantName" at 5058,-434 h60
  text "ASSEMBLY VARIANT:" at 6097,-434 h60
  text ".VersionControl_RevNumber" at 1035.5,-656.17 h60
  text "SVN REV:" at 1541.5,-656.17 h60
  text ".PCB_Rev" at 2088,-656.17 h60
  text "REV:" at 2379.5,-656.17 h60
  text ".PRJ_Number" at 3224,-656.17 h60
  text "BOARD #:" at 3769.5,-656.17 h60
  text "PCB VIEWED FROM BOTTOM SIDE" at 6246,-656.17 h60
  text ".TID" at 3224,-859.5 h60
  text "TID #:" at 3769.5,-859.5 h60
  text "TEXAS INSTRUMENTS" at 904.5,-1064.84 h60
  text ".Print_Time" at 2169,-1064.84 h60
  text ".Print_Date" at 2898,-1064.84 h60
  text "GENERATED    :" at 3767.5,-1064.84 h60
  text ".plot_File_Name" at 5440.5,-1064.84 h60
  text "PLOT NAME =" at 6246,-1064.84 h60
M9 Title Sheet:
  drawing of 57 lines, arcs and shapes, not listed
  text "1" at 739.84,8036.5 h70
  text "2" at 3235.5,8036.5 h70
  text "3" at 5724.84,8036.5 h70
  text "4" at 8231.51,8036.5 h70
  text "5" at 10730.5,8036.5 h70
  text "6" at 13235.5,8036.5 h70
  text "A" at -416.5,6893.5 h70
  text "A" at 14383.5,6893.5 h70
  text "B" at -416.5,4513.5 h70
  text "B" at 14383.5,4513.5 h70
  text "C" at -416.5,2138.5 h70
  text "C" at 14383.5,2138.5 h70
  text "PROJECT TITLE:" at 11343.5,277.5 h45
  text ".PRJ_Title" at 11393.5,144.17 h70
  text "DESIGNED FOR:" at 11343.5,-23.5 h45
  text ".PRJ_Customer" at 11393.5,-163.5 h70
  text "D" at -416.5,-231.5 h70
  text "D" at 14383.5,-231.5 h70
  text "FILE NAME:" at 11343.5,-323.5 h45
  text ".PCB_File_Name_No_Path" at 11393.5,-443.5 h70
  text "Texas Instruments (TI) and/or its licensors do not warrant the accuracy or completeness of this specification" at 6374,-605.34 h45
  text "ENGINEER:" at 11343.5,-613.5 h45
  text "LAYOUT BY:" at 12848.5,-613.5 h45
  text "or any information contained therein. TI and/or its licensors do not warrant that this design will meet" at 6329.01,-718 h45
  text ".PRJ_Engineer" at 11393.5,-768.49 h70
  text ".PCB_Layout" at 12899,-768.49 h70
  text "the specifications, will be suitable for your application or fit for any particular purpose, or will operate in" at 6329.01,-830.67 h45
  text ".Layer_Name" at 577,-858.49 h60
  text "ALTIUM DESIGNER VERSION:" at 12848.5,-923.5 h45
  text "an implementation. TI and/or its licensors do not warrant that the design is production worthy. You should" at 6329.01,-943.33 h45
  text "completely validate and test your design implementation to confirm the system functionality for your application." at 6374,-1056 h45
  text ".print_Scale" at 11393.5,-1056.83 h70
  text ".Application_BuildNumber" at 12899,-1056.83 h70
  text "1" at 739.84,-1263.5 h70
  text "2" at 3235.5,-1263.5 h70
  text "3" at 5724.84,-1263.5 h70
  text "4" at 8231.51,-1263.5 h70
  text "5" at 10730.5,-1263.5 h70
  text "6" at 13235.5,-1263.5 h70
M10 Fab Notes:
  drawing of 189 lines, arcs and shapes, not listed
  text "DESIGN INFORMATION" at 12382.02,6356.17 h60
  text "MIN. TRACK WIDTH:" at 11737.46,6224.05 h60
  text "8" at 12833.7,6224.05 h60
  text "MIL" at 12988.46,6224.05 h60
  text "MIN. CLEARANCE:" at 11737.46,6099.92 h60
  text "0.2" at 12773.7,6099.93 h60
  text "mm" at 12988.46,6099.92 h60
  text "MIN. VIA PAD SIZE:" at 11737.46,5975.8 h60
  text "24" at 12803.71,5975.8 h60
  text "MIL" at 12988.46,5975.8 h60
  text "0.05mm (2MIL)" at 12432.46,5845.9 h60
  text "MINIMUM ANNULAR RING" at 11408.23,5837.67 h60
  text "EXTERNAL" at 13140.46,5837.67 h60
  text "PER" at 11608.23,5727.55 h60
  text "IPC-D-275 CLASS 2 LEVEL C" at 11828.23,5727.54 h60
  text "MIL, HOLES" at 13316.46,5627.07 h60
  text "+/-" at 12924,5618.48 h60
  text "+/-" at 13778,5618.48 h60
  text "REGISTRATION TOLERANCES:" at 11408.23,5617.42 h60
  text "METAL" at 12608,5617.42 h60
  text "5" at 13184.2,5617.42 h60
  text "3" at 14017.2,5617.42 h60
  text "MIL" at 14133.46,5617.42 h60
  text "HOLE SIZE TOLERANCE (UNLESS OTHERWISE SPECIFIED):" at 11408.23,5519.1 h60
  text "+/-" at 13778,5516.23 h60
  text "3" at 14017.2,5515.17 h60
  text "MIL" at 14133.46,5515.17 h60
  text "MATERIAL:" at 11333.46,5377.52 h60
  text "FR-4 High Tg" at 12319.9,5249 h60
  text "X" at 12175.46,5241.01 h60
  text "FR-408" at 11754.46,5236.49 h60
  text "OTHER" at 13242.46,5236.49 h60
  text "40.4 MIL (1.0mm) +/-10%" at 12074.56,5093.46 h60
  text "X" at 11955,5090 h60
  text "40MIL" at 13725,5086 h72
  text "THICKNESS:" at 11408.23,5085.24 h60
  text "OTHER" at 13359.46,5085.24 h60
  text "TOLERANCE:" at 11408.23,4946.92 h60
  text "X" at 12256.46,4946.92 h60
  text "ANSI IPC-6012 TYPE 3 CLASS 2" at 12434.48,4946.92 h60
  text "OTHER +/-" at 12434.46,4802.73 h60
  text "BOW & TWIST:" at 11408.23,4657.54 h60
  text "X" at 12256.46,4657.54 h60
  text "ANSI IPC-6012 TYPE 3 CLASS 2" at 12434.48,4657.54 h60
  text "OTHER +/-" at 12434.46,4510.85 h60
  text "DRILLING:" at 11333.46,4380.23 h60
  text "NC_DRILL FILES" at 13094.46,4275.04 h60
  text "REFERENCE:" at 11408.23,4271.1 h60
  text "X" at 12065.46,4271.01 h60
  text "AS SHOWN" at 12243.46,4271.1 h60
  text "X" at 12966.46,4271.1 h60
  text "OTHER" at 13392.46,4128.85 h60
  text "PTH COPPER THICKNESS:" at 11407.91,4125.32 h60
  text "X" at 12547.14,4125.32 h60
  text "20-30 um" at 12675.14,4125.32 h60
  text "BOARD FINISH:" at 11333.46,3977.73 h60
  text "SILKSCREEN:" at 11488.68,3867.6 h60
  text "X" at 12446.46,3867.6 h60
  text "TOP" at 12563.46,3867.6 h60
  text "X" at 12956.46,3867.6 h60
  text "BOTTOM" at 13074.46,3867.6 h60
  text "SILKSCREEN COLOR:" at 11488.68,3712.41 h60
  text "X" at 12445.46,3712.41 h60
  text "WHITE" at 12563.46,3712.41 h60
  text "OTHER" at 13074.46,3712.41 h60
  text "X" at 12576.46,3568.96 h60
  text "GREEN" at 12694.46,3568.96 h60
  text "OTHER" at 13312.46,3568.96 h60
  text "SOLDER RESIST COLOR:" at 11488.68,3562.1 h60
  text "X" at 12576.46,3414.71 h60
  text "MATTE" at 12694.46,3414.71 h60
  text "SEMI-GLOSS" at 13312,3414.07 h60
  text "IMMERSION GOLD (ENIG)" at 12394.46,3241.94 h60
  text "ENEPIG" at 13732,3234.72 h60
  text "SURFACE FINISH:" at 11333.46,3233.72 h60
  text "X" at 12216.46,3233.72 h60
  text "IMM. TIN/SILVER OR EQUIV" at 11663,3096.4 h60
  text "OTHER" at 13094.46,3092.47 h60
  text "ARRAY/PANEL:" at 11333.46,2937.09 h60
  text "CUT AND TRIM PER M1 BOARD OUTLINE" at 12394.46,2928.87 h60
  text "N.C. ROUTE" at 12394.46,2792.9 h60
  text "X" at 13082.46,2792.9 h60
  text "V. SCORE" at 13260.46,2792.9 h60
  text "CERTIFICATION:" at 11333.46,2663.77 h60
  text "MATERIALS AND WORKMANSHIP FOR ALL PCBS" at 12058.46,2663.77 h60
  text "TO MEET OR EXCEED THE REQUIREMENTS OF:" at 12058.46,2569.71 h60
  text "X" at 11695.97,2441.08 h60
  text "ANSI IPC-A-600F CLASS ->" at 11823.96,2441.08 h60
  text "X" at 13471.97,2441.08 h60
  text "2" at 13581.96,2441.08 h60
  text "1" at 13266.96,2439.58 h60
  text "3" at 13935.96,2439.58 h60
  text "X" at 12507.97,2293.39 h60
  text "RoHS" at 12635.96,2293.39 h60
  text "OTHER" at 13280.36,2293.39 h60
  text "PER ORDER" at 13677.42,2293.39 h60
  text "ALL BOARDS MUST MEET OR EXCEED UL94-V0 REQUIREMENTS." at 11361,2139.57 h60
  text "PCB MUST BEAR THE UL94V-0 UL REGISTERED MATERIAL ID NUMBER" at 11361,2023.5 h60
  text "ADDITIONAL REQUIREMENTS:" at 11333.46,1854.08 h60
  text "MICROSECTION:" at 11408.23,1746.95 h60
  text "YES" at 12313.96,1746.95 h60
  text "REQUIRED" at 13175.46,1602.62 h60
  text "BARE BOARD ELEC. TEST:" at 11408.23,1599.76 h60
  text "NONE" at 12713.96,1599.76 h60
  text "X" at 13057.46,1599.76 h60
  text "PER ORDER" at 13767.46,1599.76 h60
  text "XX MIL VIAS REQUIRE NON-CONDUCTIVE FILL AND PLANARIZE" at 11576.38,1394.82 h59
  text "XX MIL VIAS REQUIRE CONDUCTIVE FILL AND PLANARIZE" at 11584.38,1290.84 h60
  text "OUTER XX MIL VIAS REQUIRE 50 OHM SINGLE-ENDED IMPEDANCE" at 11583.39,1127.46 h58
  text "LAYER 2 & 3 (INNER LAYERS) XX MIL WIDE, XX MIL SPACE / TRACES REQUIRE 100 OHM DIFFERENTIAL IMPEDANCE" at 11575.39,891.74 h60
  text ".Layer_Name" at 577,-858.49 h60
M11 Gerber Information:
  lines w10: -292,-930.17 6308,-930.17 ; -292,-726.83 6310,-726.83 ; -292,-523.5 -292,-1133.5 3713,-1133.5 6310,-1133.5 6310,-523.5 -291.5,-523.5 -291.5,-1133.5 1284,-1133.5 ; 2173,-1133.5 2173,-523.5 ; 3440,-726.83 3440,-523.5 ; 4280,-726.83 4280,-523.5 ; 4902,-1140 4902,-937.17
  text "ALL ARTWORK VIEWED FROM TOP SIDE" at -228.5,-655.67 h60
  text "BOARD #:" at 2248,-655.67 h60
  text ".PRJ_Number" at 2793.5,-655.67 h60
  text "REV:" at 3638,-655.67 h60
  text ".PCB_Rev" at 3929.5,-655.67 h60
  text "SVN REV:" at 4476,-655.67 h60
  text ".VersionControl_RevNumber" at 4982,-655.67 h60
  text "LAYER NAME =" at -228.5,-858.49 h60
  text "TID #:" at 2248,-859 h60
  text ".TID" at 2793.5,-859 h60
  text "PLOT NAME =" at -228.5,-1064.34 h60
  text ".plot_File_Name" at 577,-1064.34 h60
  text "GENERATED    :" at 2250,-1064.34 h60
  text ".Print_Date" at 3119.5,-1064.34 h60
  text ".Print_Time" at 3848.5,-1064.34 h60
  text "TEXAS INSTRUMENTS" at 5113,-1064.34 h60
M12 Stackup:
  drawing of 295 lines, arcs and shapes, not listed
  text "Layer" at 4557.35,5101 h60
  text "Name" at 4967.26,5101 h60
  text "Material" at 5907,5101 h60
  text "Thickness" at 6766.77,5101 h60
  text "Constant" at 7416.6,5101 h60
  text "Board Layer Stack" at 7986.46,5101 h60
  text "Top Overlay" at 4967.26,4981 h60
  text "Top Solder" at 4967.26,4861 h60
  text "Solder Resist" at 5907,4861 h60
  text "0.40mil" at 6766.77,4861 h60
  text "3.5" at 7416.6,4861 h60
  text "1" at 4557.35,4741 h60
  text "Top Layer" at 4967.26,4741 h60
  text "1.40mil" at 6766.77,4741 h60
  text "Dielectric 1" at 4967.26,4621 h60
  text "FR-4" at 5907,4621 h60
  text "8.00mil" at 6766.77,4621 h60
  text "4.2" at 7416.6,4621 h60
  text "2" at 4557.35,4501 h60
  text "Signal Layer 1" at 4967.26,4501 h60
  text "1.40mil" at 6766.77,4501 h60
  text "Dielectric 2" at 4967.26,4381 h60
  text "FR-4" at 5907,4381 h60
  text "18.00mil" at 6766.77,4381 h60
  text "4.2" at 7416.6,4381 h60
  text "3" at 4557.35,4261 h60
  text "Signal Layer 2" at 4967.26,4261 h60
  text "1.40mil" at 6766.77,4261 h60
  text "Dielectric 3" at 4967.26,4141 h60
  text "FR-4" at 5907,4141 h60
  text "8.00mil" at 6766.77,4141 h60
  text "4.2" at 7416.6,4141 h60
  text "4" at 4557.35,4021 h60
  text "Bottom Layer" at 4967.26,4021 h60
  text "1.40mil" at 6766.77,4021 h60
  text "Bottom Solder" at 4967.26,3901 h60
  text "Solder Resist" at 5907,3901 h60
  text "0.40mil" at 6766.77,3901 h60
  text "3.5" at 7416.6,3901 h60
  text "Bottom Overlay" at 4967.26,3781 h60
  text ".Layer_Name" at 577,-858.49 h60
M13 Component Bodies Top:
  text ".Layer_Name" at 577,-858.49 h60
M14 Component Bodies Bottom:
  text ".Layer_Name" at 577,-858.49 h60
M15 Courtyards Top:
  text ".Layer_Name" at 577,-858.49 h60
M16 Courtyards Bottom:
  text ".Layer_Name" at 577,-858.49 h60
Drill Drawing:
  circle w10: c4398.72,3206.76 r27.63
  circle w10: c4398.72,2585.16 r16.58
  circle w10: c4398.72,2585.16 r27.63
  lines w10: 4371.09,1811.62 4426.34,1811.62 4426.34,1866.87 4371.09,1866.87 4371.09,1811.62 ; 4371.09,1949.75 4384.9,1949.75 4384.9,1935.94 4412.53,1935.94 4412.53,1949.75 4426.34,1949.75 4426.34,1977.38 4412.53,1977.38 4412.53,1991.19 4384.9,1991.19 4384.9,1977.38 4371.09,1977.38 4371.09,1949.75 ; 4371.09,2074.07 4384.9,2074.07 4398.72,2060.26 4412.53,2074.07 4426.34,2074.07 4412.53,2087.88 4426.34,2101.7 4412.53,2101.7 4398.72,2115.51 4384.9,2101.7 4371.09,2101.7 4384.9,2087.88 4371.09,2074.07 ; 4371.09,2184.58 4426.34,2184.58 4426.34,2239.83 4371.09,2239.83 4371.09,2184.58 ; 4371.09,2433.22 4398.72,2447.03 4426.34,2433.22 4412.53,2460.84 4426.34,2488.47 4398.72,2474.66 4371.09,2488.47 4384.9,2460.84 4371.09,2433.22 ; 4371.09,2709.48 4398.72,2681.86 4426.34,2709.48 4398.72,2737.11 4371.09,2709.48 ; 4371.09,2861.43 4426.34,2861.43 4398.72,2806.18 4371.09,2861.43 ; 4371.09,3054.82 4398.72,3068.63 4426.34,3054.82 4412.53,3082.44 4426.34,3110.07 4398.72,3096.26 4371.09,3110.07 4384.9,3082.44 4371.09,3054.82 ; 4382.14,1822.67 4415.29,1822.67 4415.29,1855.82 4382.14,1855.82 4382.14,1822.67 ; 4382.14,3065.87 4398.72,3074.15 4415.29,3065.87 4407.01,3082.44 4415.29,3099.02 4398.72,3090.73 4382.14,3099.02 4390.43,3082.44 4382.14,3065.87
  lines w12: 4321,1774.32 7473.26,1774.32 ; 4321,3390.48 7473.26,3390.48 ; 4658.86,1650 4658.86,3514.8 ; 4958.28,1650 4958.28,3514.8 ; 5548.19,1650 5548.19,3514.8 ; 5807.33,1650 5807.33,3514.8 ; 6182.49,1650 6182.49,3514.8 ; 6906.82,1650 6906.82,3514.8 ; 4321,1650 7473.26,1650 7473.26,3514.8 4321,3514.8 4321,1650
  text "Symbol" at 4395.59,3427.78 h72
  text "Count" at 4696.16,3427.78 h72
  text "Hole Size" at 4995.58,3427.78 h72
  text "Plated" at 5585.49,3427.78 h72
  text "Hole Type" at 5844.63,3427.78 h72
  text "Drill Layer Pair" at 6219.79,3427.78 h72
  text "Hole Tolerance" at 6944.12,3427.78 h72
  text "5" at 4696.16,3303.46 h60
  text "7.87mil (0.200mm)" at 4995.58,3303.46 h60
  text "PTH" at 5585.49,3303.46 h60
  text "Round" at 5844.63,3303.46 h60
  text "Top Layer - Bottom Layer" at 6219.79,3303.46 h60
  text "D" at 4370.31,3293.47 h55.25
  text "15" at 4696.16,3179.14 h60
  text "8.00mil (0.203mm)" at 4995.58,3179.14 h60
  text "PTH" at 5585.49,3179.14 h60
  text "Round" at 5844.63,3179.14 h60
  text "Top Layer - Bottom Layer" at 6219.79,3179.14 h60
  text "56" at 4696.16,3054.82 h60
  text "11.81mil (0.300mm)" at 4995.58,3054.82 h60
  text "PTH" at 5585.49,3054.82 h60
  text "Round" at 5844.63,3054.82 h60
  text "Top Layer - Bottom Layer" at 6219.79,3054.82 h60
  text "2" at 4696.16,2930.5 h60
  text "25.59mil (0.650mm)" at 4995.58,2930.5 h60
  text "PTH" at 5585.49,2930.5 h60
  text "Round" at 5844.63,2930.5 h60
  text "Top Layer - Bottom Layer" at 6219.79,2930.5 h60
  text "C" at 4370.31,2920.51 h55.25
  text "14" at 4696.16,2806.18 h60
  text "31.50mil (0.800mm)" at 4995.58,2806.18 h60
  text "PTH" at 5585.49,2806.18 h60
  text "Round" at 5844.63,2806.18 h60
  text "Top Layer - Bottom Layer" at 6219.79,2806.18 h60
  text "6" at 4696.16,2681.86 h60
  text "33.47mil (0.850mm)" at 4995.58,2681.86 h60
  text "PTH" at 5585.49,2681.86 h60
  text "Round" at 5844.63,2681.86 h60
  text "Top Layer - Bottom Layer" at 6219.79,2681.86 h60
  text "2" at 4696.16,2557.54 h60
  text "35.43mil (0.900mm)" at 4995.58,2557.54 h60
  text "PTH" at 5585.49,2557.54 h60
  text "Round" at 5844.63,2557.54 h60
  text "Top Layer - Bottom Layer" at 6219.79,2557.54 h60
  text "2" at 4696.16,2433.22 h60
  text "37.40mil (0.950mm)" at 4995.58,2433.22 h60
  text "PTH" at 5585.49,2433.22 h60
  text "Round" at 5844.63,2433.22 h60
  text "Top Layer - Bottom Layer" at 6219.79,2433.22 h60
  text "2" at 4696.16,2308.9 h60
  text "41.34mil (1.050mm)" at 4995.58,2308.9 h60
  text "PTH" at 5585.49,2308.9 h60
  text "Round" at 5844.63,2308.9 h60
  text "Top Layer - Bottom Layer" at 6219.79,2308.9 h60
  text "A" at 4370.31,2298.91 h55.25
  text "6" at 4696.16,2184.58 h60
  text "49.21mil (1.250mm)" at 4995.58,2184.58 h60
  text "PTH" at 5585.49,2184.58 h60
  text "Round" at 5844.63,2184.58 h60
  text "Top Layer - Bottom Layer" at 6219.79,2184.58 h60
  text "4" at 4696.16,2060.26 h60
  text "53.15mil (1.350mm)" at 4995.58,2060.26 h60
  text "PTH" at 5585.49,2060.26 h60
  text "Round" at 5844.63,2060.26 h60
  text "Top Layer - Bottom Layer" at 6219.79,2060.26 h60
  text "3" at 4696.16,1935.94 h60
  text "63.00mil (1.600mm)" at 4995.58,1935.94 h60
  text "PTH" at 5585.49,1935.94 h60
  text "Round" at 5844.63,1935.94 h60
  text "Top Layer - Bottom Layer" at 6219.79,1935.94 h60
  text "4" at 4696.16,1811.62 h60
  text "118.11mil (3.000mm)" at 4995.58,1811.62 h60
  text "PTH" at 5585.49,1811.62 h60
  text "Round" at 5844.63,1811.62 h60
  text "Top Layer - Bottom Layer" at 6219.79,1811.62 h60
  text "121 Total" at 4696.16,1687.3 h60
  text ".Layer_Name" at 577,-858.49 h60
Mechanical 17:
  text ".Layer_Name" at 577,-858.49 h60
Mechanical 18:
  text ".Layer_Name" at 577,-858.49 h60
Mechanical 19:
  text ".Layer_Name" at 577,-858.49 h60

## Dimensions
0,-400 to 1000,-400 on M2 Board Dimensions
